VERSION 5.8 ;
BUSBITCHARS "[]" ;
DIVIDERCHAR "/" ;
UNITS
    DATABASE MICRONS 1000 ;
END UNITS

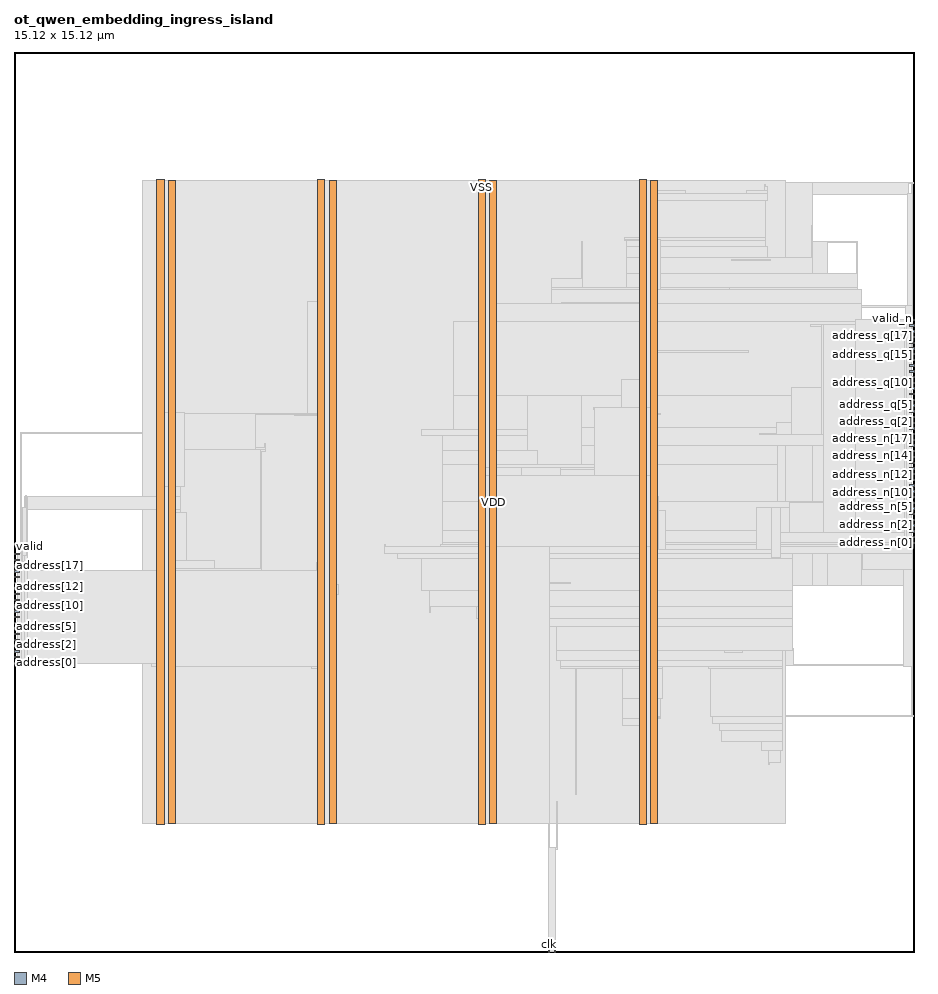
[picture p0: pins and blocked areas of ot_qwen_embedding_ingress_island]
MACRO ot_qwen_embedding_ingress_island
  FOREIGN ot_qwen_embedding_ingress_island 0 0 ;
  CLASS BLOCK ;
  SIZE 15.12 BY 15.12 ;
  PIN address[0]
    DIRECTION INPUT ;
    USE SIGNAL ;
    PORT
      LAYER M4 ;
        RECT  0 4.848 0.084 4.872 ;
    END
  END address[0]
  PIN address[10]
    DIRECTION INPUT ;
    USE SIGNAL ;
    PORT
      LAYER M4 ;
        RECT  0 5.808 0.084 5.832 ;
    END
  END address[10]
  PIN address[11]
    DIRECTION INPUT ;
    USE SIGNAL ;
    PORT
      LAYER M4 ;
        RECT  0 5.904 0.084 5.928 ;
    END
  END address[11]
  PIN address[12]
    DIRECTION INPUT ;
    USE SIGNAL ;
    PORT
      LAYER M4 ;
        RECT  0 6 0.084 6.024 ;
    END
  END address[12]
  PIN address[13]
    DIRECTION INPUT ;
    USE SIGNAL ;
    PORT
      LAYER M4 ;
        RECT  0 6.096 0.084 6.12 ;
    END
  END address[13]
  PIN address[14]
    DIRECTION INPUT ;
    USE SIGNAL ;
    PORT
      LAYER M4 ;
        RECT  0 6.192 0.084 6.216 ;
    END
  END address[14]
  PIN address[15]
    DIRECTION INPUT ;
    USE SIGNAL ;
    PORT
      LAYER M4 ;
        RECT  0 6.288 0.084 6.312 ;
    END
  END address[15]
  PIN address[16]
    DIRECTION INPUT ;
    USE SIGNAL ;
    PORT
      LAYER M4 ;
        RECT  0 6.384 0.084 6.408 ;
    END
  END address[16]
  PIN address[17]
    DIRECTION INPUT ;
    USE SIGNAL ;
    PORT
      LAYER M4 ;
        RECT  0 6.48 0.084 6.504 ;
    END
  END address[17]
  PIN address[1]
    DIRECTION INPUT ;
    USE SIGNAL ;
    PORT
      LAYER M4 ;
        RECT  0 4.944 0.084 4.968 ;
    END
  END address[1]
  PIN address[2]
    DIRECTION INPUT ;
    USE SIGNAL ;
    PORT
      LAYER M4 ;
        RECT  0 5.04 0.084 5.064 ;
    END
  END address[2]
  PIN address[3]
    DIRECTION INPUT ;
    USE SIGNAL ;
    PORT
      LAYER M4 ;
        RECT  0 5.136 0.084 5.16 ;
    END
  END address[3]
  PIN address[4]
    DIRECTION INPUT ;
    USE SIGNAL ;
    PORT
      LAYER M4 ;
        RECT  0 5.232 0.084 5.256 ;
    END
  END address[4]
  PIN address[5]
    DIRECTION INPUT ;
    USE SIGNAL ;
    PORT
      LAYER M4 ;
        RECT  0 5.328 0.084 5.352 ;
    END
  END address[5]
  PIN address[6]
    DIRECTION INPUT ;
    USE SIGNAL ;
    PORT
      LAYER M4 ;
        RECT  0 5.424 0.084 5.448 ;
    END
  END address[6]
  PIN address[7]
    DIRECTION INPUT ;
    USE SIGNAL ;
    PORT
      LAYER M4 ;
        RECT  0 5.52 0.084 5.544 ;
    END
  END address[7]
  PIN address[8]
    DIRECTION INPUT ;
    USE SIGNAL ;
    PORT
      LAYER M4 ;
        RECT  0 5.616 0.084 5.64 ;
    END
  END address[8]
  PIN address[9]
    DIRECTION INPUT ;
    USE SIGNAL ;
    PORT
      LAYER M4 ;
        RECT  0 5.712 0.084 5.736 ;
    END
  END address[9]
  PIN address_n[0]
    DIRECTION OUTPUT ;
    USE SIGNAL ;
    PORT
      LAYER M4 ;
        RECT  15.036 6.864 15.12 6.888 ;
    END
  END address_n[0]
  PIN address_n[10]
    DIRECTION OUTPUT ;
    USE SIGNAL ;
    PORT
      LAYER M4 ;
        RECT  15.036 7.824 15.12 7.848 ;
    END
  END address_n[10]
  PIN address_n[11]
    DIRECTION OUTPUT ;
    USE SIGNAL ;
    PORT
      LAYER M4 ;
        RECT  15.036 7.92 15.12 7.944 ;
    END
  END address_n[11]
  PIN address_n[12]
    DIRECTION OUTPUT ;
    USE SIGNAL ;
    PORT
      LAYER M4 ;
        RECT  15.036 8.016 15.12 8.04 ;
    END
  END address_n[12]
  PIN address_n[13]
    DIRECTION OUTPUT ;
    USE SIGNAL ;
    PORT
      LAYER M4 ;
        RECT  15.036 8.112 15.12 8.136 ;
    END
  END address_n[13]
  PIN address_n[14]
    DIRECTION OUTPUT ;
    USE SIGNAL ;
    PORT
      LAYER M4 ;
        RECT  15.036 8.208 15.12 8.232 ;
    END
  END address_n[14]
  PIN address_n[15]
    DIRECTION OUTPUT ;
    USE SIGNAL ;
    PORT
      LAYER M4 ;
        RECT  15.036 8.304 15.12 8.328 ;
    END
  END address_n[15]
  PIN address_n[16]
    DIRECTION OUTPUT ;
    USE SIGNAL ;
    PORT
      LAYER M4 ;
        RECT  15.036 8.4 15.12 8.424 ;
    END
  END address_n[16]
  PIN address_n[17]
    DIRECTION OUTPUT ;
    USE SIGNAL ;
    PORT
      LAYER M4 ;
        RECT  15.036 8.496 15.12 8.52 ;
    END
  END address_n[17]
  PIN address_n[1]
    DIRECTION OUTPUT ;
    USE SIGNAL ;
    PORT
      LAYER M4 ;
        RECT  15.036 6.96 15.12 6.984 ;
    END
  END address_n[1]
  PIN address_n[2]
    DIRECTION OUTPUT ;
    USE SIGNAL ;
    PORT
      LAYER M4 ;
        RECT  15.036 7.056 15.12 7.08 ;
    END
  END address_n[2]
  PIN address_n[3]
    DIRECTION OUTPUT ;
    USE SIGNAL ;
    PORT
      LAYER M4 ;
        RECT  15.036 7.152 15.12 7.176 ;
    END
  END address_n[3]
  PIN address_n[4]
    DIRECTION OUTPUT ;
    USE SIGNAL ;
    PORT
      LAYER M4 ;
        RECT  15.036 7.248 15.12 7.272 ;
    END
  END address_n[4]
  PIN address_n[5]
    DIRECTION OUTPUT ;
    USE SIGNAL ;
    PORT
      LAYER M4 ;
        RECT  15.036 7.344 15.12 7.368 ;
    END
  END address_n[5]
  PIN address_n[6]
    DIRECTION OUTPUT ;
    USE SIGNAL ;
    PORT
      LAYER M4 ;
        RECT  15.036 7.44 15.12 7.464 ;
    END
  END address_n[6]
  PIN address_n[7]
    DIRECTION OUTPUT ;
    USE SIGNAL ;
    PORT
      LAYER M4 ;
        RECT  15.036 7.536 15.12 7.56 ;
    END
  END address_n[7]
  PIN address_n[8]
    DIRECTION OUTPUT ;
    USE SIGNAL ;
    PORT
      LAYER M4 ;
        RECT  15.036 7.632 15.12 7.656 ;
    END
  END address_n[8]
  PIN address_n[9]
    DIRECTION OUTPUT ;
    USE SIGNAL ;
    PORT
      LAYER M4 ;
        RECT  15.036 7.728 15.12 7.752 ;
    END
  END address_n[9]
  PIN address_q[0]
    DIRECTION OUTPUT ;
    USE SIGNAL ;
    PORT
      LAYER M4 ;
        RECT  15.036 8.592 15.12 8.616 ;
    END
  END address_q[0]
  PIN address_q[10]
    DIRECTION OUTPUT ;
    USE SIGNAL ;
    PORT
      LAYER M4 ;
        RECT  15.036 9.552 15.12 9.576 ;
    END
  END address_q[10]
  PIN address_q[11]
    DIRECTION OUTPUT ;
    USE SIGNAL ;
    PORT
      LAYER M4 ;
        RECT  15.036 9.648 15.12 9.672 ;
    END
  END address_q[11]
  PIN address_q[12]
    DIRECTION OUTPUT ;
    USE SIGNAL ;
    PORT
      LAYER M4 ;
        RECT  15.036 9.744 15.12 9.768 ;
    END
  END address_q[12]
  PIN address_q[13]
    DIRECTION OUTPUT ;
    USE SIGNAL ;
    PORT
      LAYER M4 ;
        RECT  15.036 9.84 15.12 9.864 ;
    END
  END address_q[13]
  PIN address_q[14]
    DIRECTION OUTPUT ;
    USE SIGNAL ;
    PORT
      LAYER M4 ;
        RECT  15.036 9.936 15.12 9.96 ;
    END
  END address_q[14]
  PIN address_q[15]
    DIRECTION OUTPUT ;
    USE SIGNAL ;
    PORT
      LAYER M4 ;
        RECT  15.036 10.032 15.12 10.056 ;
    END
  END address_q[15]
  PIN address_q[16]
    DIRECTION OUTPUT ;
    USE SIGNAL ;
    PORT
      LAYER M4 ;
        RECT  15.036 10.128 15.12 10.152 ;
    END
  END address_q[16]
  PIN address_q[17]
    DIRECTION OUTPUT ;
    USE SIGNAL ;
    PORT
      LAYER M4 ;
        RECT  15.036 10.224 15.12 10.248 ;
    END
  END address_q[17]
  PIN address_q[1]
    DIRECTION OUTPUT ;
    USE SIGNAL ;
    PORT
      LAYER M4 ;
        RECT  15.036 8.688 15.12 8.712 ;
    END
  END address_q[1]
  PIN address_q[2]
    DIRECTION OUTPUT ;
    USE SIGNAL ;
    PORT
      LAYER M4 ;
        RECT  15.036 8.784 15.12 8.808 ;
    END
  END address_q[2]
  PIN address_q[3]
    DIRECTION OUTPUT ;
    USE SIGNAL ;
    PORT
      LAYER M4 ;
        RECT  15.036 8.88 15.12 8.904 ;
    END
  END address_q[3]
  PIN address_q[4]
    DIRECTION OUTPUT ;
    USE SIGNAL ;
    PORT
      LAYER M4 ;
        RECT  15.036 8.976 15.12 9 ;
    END
  END address_q[4]
  PIN address_q[5]
    DIRECTION OUTPUT ;
    USE SIGNAL ;
    PORT
      LAYER M4 ;
        RECT  15.036 9.072 15.12 9.096 ;
    END
  END address_q[5]
  PIN address_q[6]
    DIRECTION OUTPUT ;
    USE SIGNAL ;
    PORT
      LAYER M4 ;
        RECT  15.036 9.168 15.12 9.192 ;
    END
  END address_q[6]
  PIN address_q[7]
    DIRECTION OUTPUT ;
    USE SIGNAL ;
    PORT
      LAYER M4 ;
        RECT  15.036 9.264 15.12 9.288 ;
    END
  END address_q[7]
  PIN address_q[8]
    DIRECTION OUTPUT ;
    USE SIGNAL ;
    PORT
      LAYER M4 ;
        RECT  15.036 9.36 15.12 9.384 ;
    END
  END address_q[8]
  PIN address_q[9]
    DIRECTION OUTPUT ;
    USE SIGNAL ;
    PORT
      LAYER M4 ;
        RECT  15.036 9.456 15.12 9.48 ;
    END
  END address_q[9]
  PIN clk
    DIRECTION INPUT ;
    USE SIGNAL ;
    PORT
      LAYER M5 ;
        RECT  8.976 0 9 0.084 ;
    END
  END clk
  PIN credit
    DIRECTION INPUT ;
    USE SIGNAL ;
    PORT
      LAYER M4 ;
        RECT  0 6.576 0.084 6.6 ;
    END
  END credit
  PIN credit_n
    DIRECTION OUTPUT ;
    USE SIGNAL ;
    PORT
      LAYER M4 ;
        RECT  15.036 10.32 15.12 10.344 ;
    END
  END credit_n
  PIN credit_q
    DIRECTION OUTPUT ;
    USE SIGNAL ;
    PORT
      LAYER M4 ;
        RECT  15.036 10.416 15.12 10.44 ;
    END
  END credit_q
  PIN rst_n
    DIRECTION INPUT ;
    USE SIGNAL ;
    PORT
      LAYER M5 ;
        RECT  9.072 0 9.096 0.084 ;
    END
  END rst_n
  PIN valid
    DIRECTION INPUT ;
    USE SIGNAL ;
    PORT
      LAYER M4 ;
        RECT  0 6.672 0.084 6.696 ;
    END
  END valid
  PIN valid_n
    DIRECTION OUTPUT ;
    USE SIGNAL ;
    PORT
      LAYER M4 ;
        RECT  15.036 10.512 15.12 10.536 ;
    END
  END valid_n
  PIN valid_q
    DIRECTION OUTPUT ;
    USE SIGNAL ;
    PORT
      LAYER M4 ;
        RECT  15.036 10.608 15.12 10.632 ;
    END
  END valid_q
  PIN VDD
    DIRECTION INOUT ;
    USE POWER ;
    PORT
      LAYER M5 ;
        RECT  10.692 2.151 10.812 12.969 ;
        RECT  7.992 2.151 8.112 12.969 ;
        RECT  5.292 2.151 5.412 12.969 ;
        RECT  2.592 2.151 2.712 12.969 ;
    END
  END VDD
  PIN VSS
    DIRECTION INOUT ;
    USE GROUND ;
    PORT
      LAYER M5 ;
        RECT  10.5 2.137 10.62 12.983 ;
        RECT  7.8 2.137 7.92 12.983 ;
        RECT  5.1 2.137 5.22 12.983 ;
        RECT  2.4 2.137 2.52 12.983 ;
    END
  END VSS
  OBS
    LAYER RVTN ;
     RECT  2.16 2.16 12.96 2.295 ;
     RECT  2.16 2.565 12.96 2.835 ;
     RECT  2.16 3.105 12.96 3.375 ;
     RECT  2.16 3.645 12.96 3.915 ;
     RECT  2.16 4.185 12.96 4.455 ;
     RECT  2.16 4.725 12.96 4.995 ;
     RECT  2.16 5.265 12.96 5.535 ;
     RECT  2.16 5.805 12.96 6.075 ;
     RECT  2.16 6.345 12.96 6.615 ;
     RECT  2.16 6.885 12.96 7.155 ;
     RECT  2.16 7.425 12.96 7.695 ;
     RECT  2.16 7.965 12.96 8.235 ;
     RECT  2.16 8.505 12.96 8.775 ;
     RECT  2.16 9.045 12.96 9.315 ;
     RECT  2.16 9.585 12.96 9.855 ;
     RECT  2.16 10.125 12.96 10.395 ;
     RECT  2.16 10.665 12.96 10.935 ;
     RECT  2.16 11.205 12.96 11.475 ;
     RECT  2.16 11.745 12.96 12.015 ;
     RECT  2.16 12.285 12.96 12.555 ;
     RECT  2.16 12.825 12.96 12.96 ;
    LAYER RVTP ;
     RECT  2.16 2.295 12.96 2.565 ;
     RECT  2.16 2.835 12.96 3.105 ;
     RECT  2.16 3.375 12.96 3.645 ;
     RECT  2.16 3.915 12.96 4.185 ;
     RECT  2.16 4.455 12.96 4.725 ;
     RECT  2.16 4.995 12.96 5.265 ;
     RECT  2.16 5.535 12.96 5.805 ;
     RECT  2.16 6.075 12.96 6.345 ;
     RECT  2.16 6.615 12.96 6.885 ;
     RECT  2.16 7.155 12.96 7.425 ;
     RECT  2.16 7.695 12.96 7.965 ;
     RECT  2.16 8.235 12.96 8.505 ;
     RECT  2.16 8.775 12.96 9.045 ;
     RECT  2.16 9.315 12.96 9.585 ;
     RECT  2.16 9.855 12.96 10.125 ;
     RECT  2.16 10.395 12.96 10.665 ;
     RECT  2.16 10.935 12.96 11.205 ;
     RECT  2.16 11.475 12.96 11.745 ;
     RECT  2.16 12.015 12.96 12.285 ;
     RECT  2.16 12.555 12.96 12.825 ;
    LAYER M1 ;
     RECT  2.16 2.151 12.96 12.969 ;
    LAYER M2 ;
     RECT  0.103 5.166 0.203 5.679 ;
     RECT  0.203 5.166 2.16 5.184 ;
     RECT  0.103 8.712 2.16 8.73 ;
     RECT  2.16 2.151 12.96 12.969 ;
     RECT  12.96 4.806 13.091 5.094 ;
     RECT  12.96 6.156 13.415 12.924 ;
     RECT  13.415 6.156 13.667 11.934 ;
     RECT  13.667 7.938 14.171 11.124 ;
     RECT  13.667 11.916 14.171 11.934 ;
     RECT  14.171 7.938 14.207 8.964 ;
     RECT  14.171 9.756 14.207 11.124 ;
     RECT  13.667 6.156 14.243 7.182 ;
     RECT  14.207 7.938 14.243 8.154 ;
     RECT  14.207 8.946 14.243 8.964 ;
     RECT  14.207 9.756 14.243 9.774 ;
     RECT  14.207 10.836 14.243 11.124 ;
     RECT  13.091 4.806 14.963 4.824 ;
     RECT  14.243 6.156 14.971 6.84 ;
     RECT  14.243 10.836 14.999 10.854 ;
     RECT  13.415 12.726 15.035 12.924 ;
     RECT  14.971 6.156 15.071 7.074 ;
     RECT  12.96 3.96 15.107 3.978 ;
     RECT  15.071 6.858 15.107 6.876 ;
     RECT  15.007 10.134 15.107 10.152 ;
     RECT  15.035 12.906 15.107 12.924 ;
    LAYER M3 ;
     RECT  2.415 2.143 2.505 2.413 ;
     RECT  5.115 2.143 5.205 2.413 ;
     RECT  7.815 2.143 7.905 2.413 ;
     RECT  10.515 2.143 10.605 2.413 ;
     RECT  9.108 1.723 9.126 2.525 ;
     RECT  12.672 3.145 12.69 3.181 ;
     RECT  12.672 3.181 12.87 3.379 ;
     RECT  12.564 3.379 12.906 3.541 ;
     RECT  11.88 3.541 12.906 3.721 ;
     RECT  10.515 2.413 10.797 3.811 ;
     RECT  11.844 3.721 12.906 3.847 ;
     RECT  10.224 3.811 10.797 3.931 ;
     RECT  11.736 3.847 12.906 3.955 ;
     RECT  10.224 3.931 10.854 4.261 ;
     RECT  5.115 2.413 5.397 4.765 ;
     RECT  9.432 2.641 9.45 4.765 ;
     RECT  10.224 4.261 10.89 4.765 ;
     RECT  11.7 3.955 12.906 4.765 ;
     RECT  2.415 2.413 2.697 4.801 ;
     RECT  9.18 4.765 10.89 4.801 ;
     RECT  11.664 4.765 12.906 4.801 ;
     RECT  15.084 3.955 15.102 4.801 ;
     RECT  9.18 4.801 12.906 4.891 ;
     RECT  5.004 4.765 5.397 4.927 ;
     RECT  9.108 4.891 12.906 5.071 ;
     RECT  4.572 4.927 5.397 5.161 ;
     RECT  4.464 5.161 5.397 5.431 ;
     RECT  7.815 2.413 8.097 5.467 ;
     RECT  9.108 5.071 13.086 5.467 ;
     RECT  0.108 5.131 0.126 5.563 ;
     RECT  7.815 5.467 13.086 5.611 ;
     RECT  0.108 5.563 0.198 5.684 ;
     RECT  2.304 4.801 2.697 5.803 ;
     RECT  3.852 5.431 5.397 5.803 ;
     RECT  6.984 5.701 7.002 5.809 ;
     RECT  7.776 5.611 13.086 5.809 ;
     RECT  0.144 5.684 0.162 5.885 ;
     RECT  2.304 5.803 5.397 5.999 ;
     RECT  5.076 5.999 5.397 6.007 ;
     RECT  2.304 5.999 4.194 6.035 ;
     RECT  6.984 5.809 13.086 6.079 ;
     RECT  2.304 6.035 4.158 6.143 ;
     RECT  5.076 6.007 5.454 6.179 ;
     RECT  14.94 4.801 15.102 6.421 ;
     RECT  2.415 6.143 4.158 6.449 ;
     RECT  5.076 6.179 5.397 6.539 ;
     RECT  2.415 6.449 3.366 6.575 ;
     RECT  6.84 6.079 13.086 6.619 ;
     RECT  6.444 6.619 13.086 6.691 ;
     RECT  14.256 6.421 15.102 6.691 ;
     RECT  6.228 6.691 15.102 6.809 ;
     RECT  6.228 6.809 6.246 6.845 ;
     RECT  7.164 6.809 15.102 6.845 ;
     RECT  7.2 6.845 15.102 6.881 ;
     RECT  7.2 6.881 15.066 7.079 ;
     RECT  2.415 6.575 2.898 7.385 ;
     RECT  2.415 7.385 2.79 7.435 ;
     RECT  7.2 7.079 14.994 7.565 ;
     RECT  2.304 7.435 2.79 7.655 ;
     RECT  2.412 7.655 2.79 7.889 ;
     RECT  2.412 7.889 2.697 7.925 ;
     RECT  7.2 7.565 12.834 8.195 ;
     RECT  13.644 7.565 14.994 8.299 ;
     RECT  4.14 6.449 4.158 8.401 ;
     RECT  7.2 8.195 8.802 8.429 ;
     RECT  4.14 8.401 4.23 8.437 ;
     RECT  4.032 8.437 4.23 8.477 ;
     RECT  9.54 8.195 12.834 8.509 ;
     RECT  13.608 8.299 14.994 8.509 ;
     RECT  4.212 8.477 4.23 8.537 ;
     RECT  7.2 8.429 8.622 8.671 ;
     RECT  0.108 6.475 0.126 8.735 ;
     RECT  6.84 8.671 8.622 8.771 ;
     RECT  9.54 8.509 14.994 8.813 ;
     RECT  5.115 6.539 5.397 9.013 ;
     RECT  4.716 9.013 5.397 9.053 ;
     RECT  7.38 8.771 8.622 9.355 ;
     RECT  9.54 8.813 14.238 9.355 ;
     RECT  14.976 8.813 14.994 10.12 ;
     RECT  14.976 10.12 15.03 10.129 ;
     RECT  7.38 9.355 14.238 10.589 ;
     RECT  14.976 10.129 15.102 10.859 ;
     RECT  7.815 10.589 14.238 10.895 ;
     RECT  4.932 9.053 5.397 10.931 ;
     RECT  9.036 10.895 14.238 11.129 ;
     RECT  9.036 11.129 14.166 11.165 ;
     RECT  9.036 11.165 9.558 11.309 ;
     RECT  10.296 11.165 14.166 11.399 ;
     RECT  10.296 11.399 13.41 11.669 ;
     RECT  10.296 11.669 12.654 11.849 ;
     RECT  9.54 11.309 9.558 11.939 ;
     RECT  14.148 11.399 14.166 11.939 ;
     RECT  10.296 11.849 12.618 11.947 ;
     RECT  10.26 11.947 12.618 12.011 ;
     RECT  13.392 11.669 13.41 12.209 ;
     RECT  10.515 12.011 12.618 12.631 ;
     RECT  2.415 7.925 2.697 12.707 ;
     RECT  5.115 10.931 5.397 12.707 ;
     RECT  7.815 10.895 8.097 12.707 ;
     RECT  10.515 12.631 12.654 12.749 ;
     RECT  15.012 10.859 15.102 12.749 ;
     RECT  10.515 12.749 11.286 12.785 ;
     RECT  12.312 12.749 12.654 12.785 ;
     RECT  12.6 12.785 12.654 12.857 ;
     RECT  12.6 12.857 12.618 12.893 ;
     RECT  15.084 12.749 15.102 12.929 ;
     RECT  2.415 12.707 2.505 12.977 ;
     RECT  5.115 12.707 5.205 12.977 ;
     RECT  7.815 12.707 7.905 12.977 ;
     RECT  10.515 12.785 10.605 12.977 ;
    LAYER M4 ;
     RECT  0.06 4.848 0.133 6.696 ;
     RECT  0.133 4.848 0.181 7.464 ;
     RECT  0.181 4.848 0.227 7.656 ;
     RECT  0.227 4.848 2.408 6.408 ;
     RECT  0.227 7.44 2.408 7.656 ;
     RECT  2.408 2.148 2.512 12.972 ;
     RECT  2.512 2.418 2.704 12.702 ;
     RECT  2.704 7.824 2.867 9.048 ;
     RECT  2.867 8.448 4.061 9.048 ;
     RECT  2.704 4.8 5.108 6.408 ;
     RECT  4.061 9.024 5.108 9.048 ;
     RECT  5.108 2.148 5.212 12.972 ;
     RECT  5.212 2.418 5.404 12.702 ;
     RECT  7.808 2.148 7.912 12.972 ;
     RECT  7.912 2.418 8.104 12.702 ;
     RECT  8.104 6.192 8.531 8.136 ;
     RECT  8.531 6.192 8.813 6.312 ;
     RECT  9.053 1.728 9.137 1.752 ;
     RECT  8.531 7.968 9.173 8.136 ;
     RECT  8.813 6.192 9.353 6.216 ;
     RECT  9.173 8.112 10.069 8.136 ;
     RECT  9.733 9.12 10.069 9.144 ;
     RECT  10.069 8.112 10.213 9.144 ;
     RECT  9.925 6.816 10.508 6.84 ;
     RECT  10.213 8.112 10.508 9.624 ;
     RECT  9.205 10.896 10.508 10.92 ;
     RECT  10.249 11.952 10.508 11.976 ;
     RECT  10.508 2.148 10.612 12.972 ;
     RECT  10.612 2.418 10.804 12.702 ;
     RECT  10.804 6.768 10.829 7.656 ;
     RECT  10.804 3.936 10.865 3.96 ;
     RECT  10.804 9.024 10.865 9.048 ;
     RECT  10.804 11.136 10.865 11.976 ;
     RECT  10.829 6.768 10.937 7.416 ;
     RECT  10.865 11.136 12.017 11.16 ;
     RECT  11.941 5.04 12.233 5.064 ;
     RECT  10.804 10.08 12.341 10.104 ;
     RECT  10.937 6.768 12.481 6.84 ;
     RECT  12.049 11.616 12.701 11.64 ;
     RECT  12.481 6.768 12.733 7.464 ;
     RECT  12.517 8.688 12.805 8.712 ;
     RECT  12.733 6.624 12.881 7.464 ;
     RECT  12.881 7.056 13.021 7.464 ;
     RECT  12.805 8.688 13.057 8.904 ;
     RECT  13.057 8.688 13.561 9.48 ;
     RECT  13.381 10.512 13.561 10.536 ;
     RECT  13.021 7.056 13.597 7.56 ;
     RECT  13.561 8.688 13.597 10.536 ;
     RECT  13.597 7.056 14.137 10.536 ;
     RECT  14.137 7.056 14.965 10.632 ;
     RECT  14.965 6.96 15.001 10.632 ;
     RECT  15.001 6.864 15.084 10.632 ;
    LAYER M5 ;
     RECT  8.976 0.016 9.096 1.763 ;
     RECT  2.4 2.137 2.52 2.151 ;
     RECT  5.1 2.137 5.22 2.151 ;
     RECT  7.8 2.137 7.92 2.151 ;
     RECT  8.976 1.763 9 2.151 ;
     RECT  10.5 2.137 10.62 2.151 ;
     RECT  0.144 6.565 0.168 6.661 ;
     RECT  7.8 2.151 9 6.805 ;
     RECT  10.5 2.151 10.812 6.805 ;
     RECT  0.144 6.661 0.216 7.475 ;
     RECT  0.192 7.475 0.216 7.667 ;
     RECT  2.4 2.151 2.712 7.813 ;
     RECT  7.8 6.805 10.812 8.003 ;
     RECT  7.8 8.003 8.52 8.147 ;
     RECT  2.4 7.813 2.856 9.059 ;
     RECT  9.744 8.003 10.812 9.155 ;
     RECT  2.4 9.059 2.712 12.969 ;
     RECT  5.1 2.151 5.412 12.969 ;
     RECT  7.8 8.147 8.112 12.969 ;
     RECT  10.5 9.155 10.812 12.969 ;
     RECT  2.4 12.969 2.52 12.983 ;
     RECT  5.1 12.969 5.22 12.983 ;
     RECT  7.8 12.969 7.92 12.983 ;
     RECT  10.5 12.969 10.62 12.983 ;
  END
END ot_qwen_embedding_ingress_island
END LIBRARY
